VERSION 5.7 ;
  NOWIREEXTENSIONATPIN ON ;
  DIVIDERCHAR "/" ;
  BUSBITCHARS "[]" ;
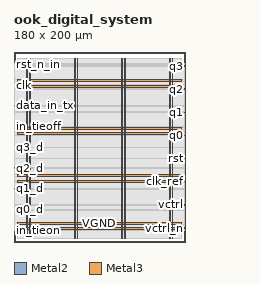
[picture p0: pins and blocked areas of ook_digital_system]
MACRO ook_digital_system
  CLASS BLOCK ;
  FOREIGN ook_digital_system ;
  ORIGIN 0.000 0.000 ;
  SIZE 180.000 BY 200.000 ;
  PIN VGND
    DIRECTION INOUT ;
    USE GROUND ;
    PORT
      LAYER Metal2 ;
        RECT 16.340 3.560 17.340 193.000 ;
    END
    PORT
      LAYER Metal2 ;
        RECT 66.340 3.560 67.340 193.000 ;
    END
    PORT
      LAYER Metal2 ;
        RECT 116.340 3.560 117.340 193.000 ;
    END
    PORT
      LAYER Metal2 ;
        RECT 166.340 3.560 167.340 193.000 ;
    END
    PORT
      LAYER Metal3 ;
        RECT 3.840 18.780 176.160 20.780 ;
    END
    PORT
      LAYER Metal3 ;
        RECT 3.840 68.780 176.160 70.780 ;
    END
    PORT
      LAYER Metal3 ;
        RECT 3.840 118.780 176.160 120.780 ;
    END
    PORT
      LAYER Metal3 ;
        RECT 3.840 168.780 176.160 170.780 ;
    END
  END VGND
  PIN VPWR
    DIRECTION INOUT ;
    USE POWER ;
    PORT
      LAYER Metal2 ;
        RECT 13.340 3.560 14.340 193.000 ;
    END
    PORT
      LAYER Metal2 ;
        RECT 63.340 3.560 64.340 193.000 ;
    END
    PORT
      LAYER Metal2 ;
        RECT 113.340 3.560 114.340 193.000 ;
    END
    PORT
      LAYER Metal2 ;
        RECT 163.340 3.560 164.340 193.000 ;
    END
    PORT
      LAYER Metal3 ;
        RECT 3.840 12.780 176.160 14.780 ;
    END
    PORT
      LAYER Metal3 ;
        RECT 3.840 62.780 176.160 64.780 ;
    END
    PORT
      LAYER Metal3 ;
        RECT 3.840 112.780 176.160 114.780 ;
    END
    PORT
      LAYER Metal3 ;
        RECT 3.840 162.780 176.160 164.780 ;
    END
  END VPWR
  PIN clk
    DIRECTION INPUT ;
    USE SIGNAL ;
    ANTENNAGATEAREA 1.450800 ;
    PORT
      LAYER Metal3 ;
        RECT 0.000 164.860 0.400 165.260 ;
    END
  END clk
  PIN clk_ref
    DIRECTION OUTPUT ;
    USE SIGNAL ;
    ANTENNADIFFAREA 0.708600 ;
    PORT
      LAYER Metal3 ;
        RECT 179.600 63.220 180.000 63.620 ;
    END
  END clk_ref
  PIN data_in_tx
    DIRECTION INPUT ;
    USE SIGNAL ;
    ANTENNAGATEAREA 0.180700 ;
    PORT
      LAYER Metal3 ;
        RECT 0.000 143.020 0.400 143.420 ;
    END
  END data_in_tx
  PIN in_tieoff
    DIRECTION OUTPUT ;
    USE SIGNAL ;
    ANTENNADIFFAREA 0.299200 ;
    PORT
      LAYER Metal3 ;
        RECT 0.000 121.180 0.400 121.580 ;
    END
  END in_tieoff
  PIN in_tieon
    DIRECTION OUTPUT ;
    USE SIGNAL ;
    ANTENNADIFFAREA 0.392700 ;
    PORT
      LAYER Metal3 ;
        RECT 0.000 11.980 0.400 12.380 ;
    END
  END in_tieon
  PIN q0
    DIRECTION INPUT ;
    USE SIGNAL ;
    ANTENNAGATEAREA 0.180700 ;
    PORT
      LAYER Metal3 ;
        RECT 179.600 111.940 180.000 112.340 ;
    END
  END q0
  PIN q0_d
    DIRECTION OUTPUT ;
    USE SIGNAL ;
    ANTENNADIFFAREA 0.708600 ;
    PORT
      LAYER Metal3 ;
        RECT 0.000 33.820 0.400 34.220 ;
    END
  END q0_d
  PIN q1
    DIRECTION INPUT ;
    USE SIGNAL ;
    ANTENNAGATEAREA 0.180700 ;
    PORT
      LAYER Metal3 ;
        RECT 179.600 136.300 180.000 136.700 ;
    END
  END q1
  PIN q1_d
    DIRECTION OUTPUT ;
    USE SIGNAL ;
    ANTENNADIFFAREA 0.708600 ;
    PORT
      LAYER Metal3 ;
        RECT 0.000 55.660 0.400 56.060 ;
    END
  END q1_d
  PIN q2
    DIRECTION INPUT ;
    USE SIGNAL ;
    ANTENNAGATEAREA 0.180700 ;
    PORT
      LAYER Metal3 ;
        RECT 179.600 160.660 180.000 161.060 ;
    END
  END q2
  PIN q2_d
    DIRECTION OUTPUT ;
    USE SIGNAL ;
    ANTENNADIFFAREA 0.708600 ;
    PORT
      LAYER Metal3 ;
        RECT 0.000 77.500 0.400 77.900 ;
    END
  END q2_d
  PIN q3
    DIRECTION INPUT ;
    USE SIGNAL ;
    ANTENNAGATEAREA 0.180700 ;
    PORT
      LAYER Metal3 ;
        RECT 179.600 185.020 180.000 185.420 ;
    END
  END q3
  PIN q3_d
    DIRECTION OUTPUT ;
    USE SIGNAL ;
    ANTENNADIFFAREA 0.708600 ;
    PORT
      LAYER Metal3 ;
        RECT 0.000 99.340 0.400 99.740 ;
    END
  END q3_d
  PIN rst
    DIRECTION OUTPUT ;
    USE SIGNAL ;
    ANTENNADIFFAREA 0.708600 ;
    PORT
      LAYER Metal3 ;
        RECT 179.600 87.580 180.000 87.980 ;
    END
  END rst
  PIN rst_n_in
    DIRECTION INPUT ;
    USE SIGNAL ;
    ANTENNAGATEAREA 0.180700 ;
    PORT
      LAYER Metal3 ;
        RECT 0.000 186.700 0.400 187.100 ;
    END
  END rst_n_in
  PIN vctrl
    DIRECTION OUTPUT ;
    USE SIGNAL ;
    ANTENNADIFFAREA 0.708600 ;
    PORT
      LAYER Metal3 ;
        RECT 179.600 38.860 180.000 39.260 ;
    END
  END vctrl
  PIN vctrl_n
    DIRECTION OUTPUT ;
    USE SIGNAL ;
    ANTENNADIFFAREA 0.708600 ;
    PORT
      LAYER Metal3 ;
        RECT 179.600 14.500 180.000 14.900 ;
    END
  END vctrl_n
  OBS
      LAYER GatPoly ;
        RECT 3.840 3.630 176.160 192.930 ;
      LAYER Metal1 ;
        RECT 3.840 3.560 176.160 193.000 ;
      LAYER Metal2 ;
        RECT 4.215 12.035 13.130 187.465 ;
        RECT 14.550 12.035 16.130 187.465 ;
        RECT 17.550 12.035 63.130 187.465 ;
        RECT 64.550 12.035 66.130 187.465 ;
        RECT 67.550 12.035 113.130 187.465 ;
        RECT 114.550 12.035 116.130 187.465 ;
        RECT 117.550 12.035 163.130 187.465 ;
        RECT 164.550 12.035 166.130 187.465 ;
        RECT 167.550 12.035 176.745 187.465 ;
      LAYER Metal3 ;
        RECT 0.400 187.310 179.600 187.420 ;
        RECT 0.610 186.490 179.600 187.310 ;
        RECT 0.400 185.630 179.600 186.490 ;
        RECT 0.400 184.810 179.390 185.630 ;
        RECT 0.400 170.990 179.600 184.810 ;
        RECT 0.400 168.570 3.630 170.990 ;
        RECT 176.370 168.570 179.600 170.990 ;
        RECT 0.400 165.470 179.600 168.570 ;
        RECT 0.610 164.990 179.600 165.470 ;
        RECT 0.610 164.650 3.630 164.990 ;
        RECT 0.400 162.570 3.630 164.650 ;
        RECT 176.370 162.570 179.600 164.990 ;
        RECT 0.400 161.270 179.600 162.570 ;
        RECT 0.400 160.450 179.390 161.270 ;
        RECT 0.400 143.630 179.600 160.450 ;
        RECT 0.610 142.810 179.600 143.630 ;
        RECT 0.400 136.910 179.600 142.810 ;
        RECT 0.400 136.090 179.390 136.910 ;
        RECT 0.400 121.790 179.600 136.090 ;
        RECT 0.610 120.990 179.600 121.790 ;
        RECT 0.610 120.970 3.630 120.990 ;
        RECT 0.400 118.570 3.630 120.970 ;
        RECT 176.370 118.570 179.600 120.990 ;
        RECT 0.400 114.990 179.600 118.570 ;
        RECT 0.400 112.570 3.630 114.990 ;
        RECT 176.370 112.570 179.600 114.990 ;
        RECT 0.400 112.550 179.600 112.570 ;
        RECT 0.400 111.730 179.390 112.550 ;
        RECT 0.400 99.950 179.600 111.730 ;
        RECT 0.610 99.130 179.600 99.950 ;
        RECT 0.400 88.190 179.600 99.130 ;
        RECT 0.400 87.370 179.390 88.190 ;
        RECT 0.400 78.110 179.600 87.370 ;
        RECT 0.610 77.290 179.600 78.110 ;
        RECT 0.400 70.990 179.600 77.290 ;
        RECT 0.400 68.570 3.630 70.990 ;
        RECT 176.370 68.570 179.600 70.990 ;
        RECT 0.400 64.990 179.600 68.570 ;
        RECT 0.400 62.570 3.630 64.990 ;
        RECT 176.370 63.830 179.600 64.990 ;
        RECT 176.370 63.010 179.390 63.830 ;
        RECT 176.370 62.570 179.600 63.010 ;
        RECT 0.400 56.270 179.600 62.570 ;
        RECT 0.610 55.450 179.600 56.270 ;
        RECT 0.400 39.470 179.600 55.450 ;
        RECT 0.400 38.650 179.390 39.470 ;
        RECT 0.400 34.430 179.600 38.650 ;
        RECT 0.610 33.610 179.600 34.430 ;
        RECT 0.400 20.990 179.600 33.610 ;
        RECT 0.400 18.570 3.630 20.990 ;
        RECT 176.370 18.570 179.600 20.990 ;
        RECT 0.400 15.110 179.600 18.570 ;
        RECT 0.400 14.990 179.390 15.110 ;
        RECT 0.400 12.590 3.630 14.990 ;
        RECT 0.610 12.570 3.630 12.590 ;
        RECT 176.370 14.290 179.390 14.990 ;
        RECT 176.370 12.570 179.600 14.290 ;
        RECT 0.610 12.080 179.600 12.570 ;
  END
END ook_digital_system
END LIBRARY

